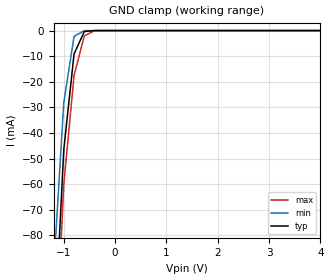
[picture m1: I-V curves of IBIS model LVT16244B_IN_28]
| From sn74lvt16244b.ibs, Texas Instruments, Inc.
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|   Model LVT16244B_IN_28
[Model]   LVT16244B_IN_28
Model_type  Input
Polarity   Non-Inverting
Vinl = 0.8
Vinh = 2.0
| variable   typ   min   max
C_comp   4p   NA   NA
[Temperature Range]   25   -40   85
[Voltage range]   2.8   2.7   2.9
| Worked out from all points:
|   GND clamp passes 1 mA (typ) near -0.61 V on its own axis
[GND Clamp]
|   Voltage   I(typ)   I(min)   I(max)
-5V       -2.158A    -2.169A    -2.264A
-1.2V     -126.5mA   -94.66mA   -144mA
-1V       -46.5mA    -28.14mA   -60.08mA
-800mV    -9.133mA   -2.237mA   -17.56mA
-600mV    -367.5uA   -43.66uA   -2.053mA
-400mV    -722.6nA   -13.95nA   -26.12uA
5V        150.8pA    8.275nA    417pA
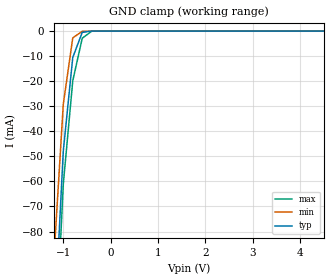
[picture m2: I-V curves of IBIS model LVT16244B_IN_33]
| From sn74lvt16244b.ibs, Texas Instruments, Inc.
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|   Model LVT16244B_IN_33
[Model]   LVT16244B_IN_33
Model_type  Input
Polarity   Non-Inverting
Vinl = 0.8
Vinh = 2.0
| variable   typ   min   max
C_comp   4p   NA   NA
[Temperature Range]   25   -40   85
[Voltage range]   3.3   3.0   3.6
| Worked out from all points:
|   GND clamp passes 1 mA (typ) near -0.61 V on its own axis
[GND Clamp]
|   Voltage   I(typ)   I(min)   I(max)
-5V       -1.808A    -1.964A    -1.81A
-1.2V     -122.6mA   -91.3mA    -140.3mA
-1V       -47.87mA   -29.15mA   -61.06mA
-800mV    -10.53mA   -2.717mA   -19.84mA
-600mV    -520.5uA   -66.75uA   -2.853mA
-400mV    -1.501uA   -57.47nA   -57.38uA
5V        654pA      352.9nA    1.202nA
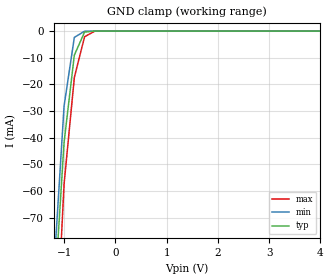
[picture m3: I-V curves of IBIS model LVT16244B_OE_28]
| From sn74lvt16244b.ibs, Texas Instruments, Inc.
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|   Model LVT16244B_OE_28
[Model]   LVT16244B_OE_28
Model_type  Input
Polarity   Non-Inverting
Vinl = 0.8
Vinh = 2.0
| variable   typ   min   max
C_comp   4p   NA   NA
[Temperature Range]   25   -40   85
[Voltage range]   2.8   2.7   2.9
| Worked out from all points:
|   GND clamp passes 1 mA (typ) near -0.61 V on its own axis
[GND Clamp]
|   Voltage   I(typ)   I(min)   I(max)
-5V       -1.782A    -1.964A    -1.89A
-1.2V     -103.1mA   -90.05mA   -134.8mA
-1V       -41.72mA   -28.1mA    -57.38mA
-800mV    -9.034mA   -2.362mA   -17.43mA
-600mV    -369.8uA   -43.6uA    -2.097mA
-400mV    -683.7nA   -55.79nA   -24.44uA
5V        543pA      94.53nA    152.2pA
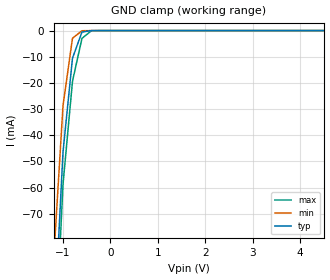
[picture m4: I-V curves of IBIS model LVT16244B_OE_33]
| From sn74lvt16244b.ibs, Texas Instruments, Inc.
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|   Model LVT16244B_OE_33
[Model]   LVT16244B_OE_33
Model_type  Input
Polarity   Non-Inverting
Vinl = 0.8
Vinh = 2.0
| variable   typ   min   max
C_comp   4p   NA   NA
[Temperature Range]   25   -40   85
[Voltage range]   3.3   3.0   3.6
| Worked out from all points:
|   GND clamp passes 1 mA (typ) near -0.61 V on its own axis
[GND Clamp]
|   Voltage   I(typ)   I(min)   I(max)
-5V       -2.067A    -2.182A    -1.86A
-1.2V     -118mA     -88.39mA   -134.3mA
-1V       -46.44mA   -28.66mA   -58.78mA
-800mV    -10.54mA   -2.926mA   -19.39mA
-600mV    -562.1uA   -66.66uA   -2.97mA
-400mV    -1.519uA   -30.87nA   -63.56uA
5V        334pA      4.395nA    173.7pA
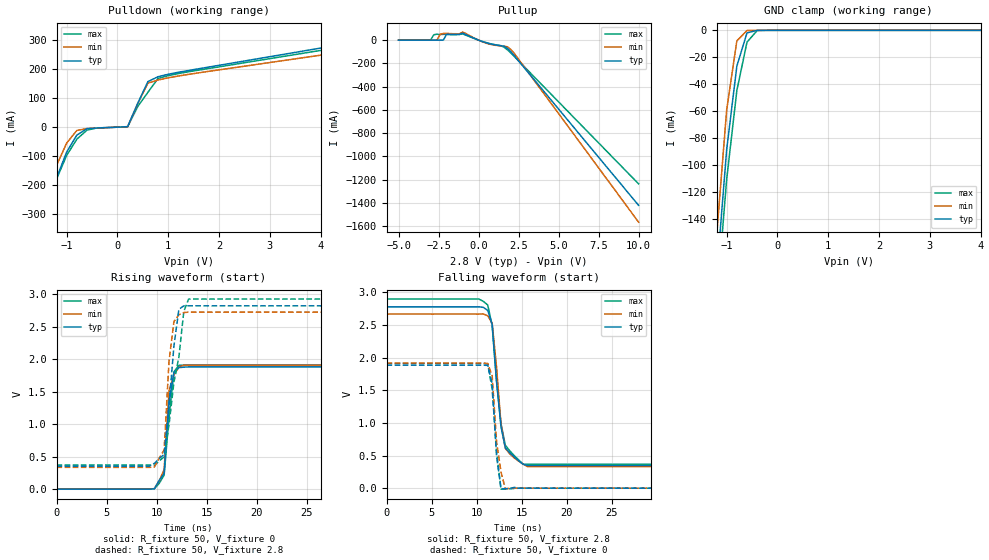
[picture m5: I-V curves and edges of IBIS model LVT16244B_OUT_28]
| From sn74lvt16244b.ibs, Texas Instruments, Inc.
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|   Model LV244A_OUT_28
[Model]   LVT16244B_OUT_28
Model_type  3-state
Polarity   Non-Inverting
Enable   Active-Low
Vmeas = 1.5
Cref = 50pf
Rref = 500
Vref = 0V
| variable   typ   min   max
C_comp   9p   NA   NA
[Temperature Range]   25   -40   85
[Voltage range]   2.8   2.7   2.9
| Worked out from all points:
|   slope of the pulldown table from 0 to 0.42 V, typ, clamps not added: 4.63 ohm
|   slope of the pullup table from 0 to 0.42 V, typ, clamps not added: 20.7 ohm
|   GND clamp passes 1 mA (typ) near -0.51 V on its own axis
|   rising waveform, R_fixture 50, V_fixture 0: 20-80 % time 606ps typ, 479ps min, 692ps max; typ from 0.004 V to 1.88 V
|   falling waveform, R_fixture 50, V_fixture 2.8: 20-80 % time 1.02ns typ, 979ps min, 1.09ns max; typ from 2.78 V to 0.35 V
|   rising waveform, R_fixture 50, V_fixture 2.8: 20-80 % time 885ps typ, 636ps min, 1.36ns max; typ from 0.357 V to 2.82 V
|   falling waveform, R_fixture 50, V_fixture 0: 20-80 % time 560ps typ, 744ps min, 646ps max; typ from 1.89 V to 0.004 V
[Pulldown]
|   Voltage   I(typ)   I(min)   I(max)
-5V       -2.032A    -1.731A    -1.883A
-1.8V     -468.9mA   -385mA     -448.5mA
-1.6V     -371.1mA   -300.8mA   -358.9mA
-1V       -86.29mA   -55.02mA   -97.82mA
-800mV    -27.55mA   -11.43mA   -41.62mA
-600mV    -5.214mA   -4.823mA   -10.29mA
200mV     1.678mA    1.694mA    1.502mA
600mV     157.7mA    152.3mA    120.7mA
800mV     174.5mA    163.2mA    168.8mA
6.4V      345.1mA    309.9mA    333.6mA
8V        392.8mA    350.6mA    379mA
10V       452.4mA    401.4mA    435.8mA
[Pullup]
|   Voltage   I(typ)   I(min)   I(max)
-5V       72.08uA    69.16uA    72.01uA
-3V       62.8uA     58.82uA    64.06uA
-2.8V     62.34uA    58.32uA    46.16mA
-2.6V     61.93uA    57.89uA    51.05mA
-2.4V     61.55uA    50.65mA    48.32mA
-2.2V     61.2uA     56.84mA    49.83mA
-2V       50.21mA    57.64mA    48.74mA
-1V       60.37mA    69.23mA    54.25mA
400mV     -19.48mA   -22.52mA   -18.42mA
1.4V      -47.56mA   -50.05mA   -48.89mA
2V        -97.67mA   -78.34mA   -108.7mA
10V       -1.422A    -1.567A    -1.237A
[GND Clamp]
|   Voltage   I(typ)   I(min)   I(max)
-5V       -2.161A    -2.101A    -1.963A
-1.2V     -183.2mA   -153.7mA   -203.3mA
-1V       -88.57mA   -59.02mA   -110.7mA
-800mV    -26.61mA   -7.837mA   -44.74mA
-600mV    -1.883mA   -140.6uA   -8.753mA
-400mV    -4.692uA   -28.08nA   -197.6uA
5V        29.91nA    20.41nA    56.24nA
[Ramp]
| variable   typ   min   max
dV/dt_r  1.134E+00/7.030E-10  1.122E+00/6.120E-10  1.182E+00/8.040E-10
dV/dt_f  1.476E+00/5.240E-10  1.413E+00/4.320E-10  1.530E+00/5.760E-10
R_load = 50
[Rising Waveform]
R_fixture = 50
V_fixture = 0
V_fixture_min = 0
V_fixture_max = 0
C_fixture = 0
L_fixture = 0
|   Time   V(typ)   V(min)   V(max)
0s        4.006mV    4.066mV    3.915mV
9.277ns   4.006mV    4.066mV    3.915mV
9.766ns   10.07mV    12.89mV    10.85mV
10.25ns   138.9mV    131.9mV    93.08mV
10.74ns   244.7mV    304.9mV    219.4mV
11.23ns   1.345V     1.518V     1.118V
11.72ns   1.798V     1.762V     1.807V
12.21ns   1.873V     1.878V     1.908V
12.7ns    1.88V      1.91V      1.91V
49.71ns   1.884V     1.91V      1.91V
[Falling Waveform]
R_fixture = 50
V_fixture = 2.8
V_fixture_min = 2.7
V_fixture_max = 2.9
C_fixture = 0pf
L_fixture = 0nH
|   Time   V(typ)   V(min)   V(max)
0s        2.777V     2.667V     2.896V
10.25ns   2.777V     2.667V     2.896V
11.23ns   2.722V     2.64V      2.805V
11.72ns   2.509V     2.527V     2.489V
12.21ns   1.638V     1.85V      1.628V
12.7ns    943mV      982.2mV    993.1mV
13.18ns   620.4mV    613.7mV    661.5mV
15.14ns   372.5mV    374.6mV    370.2mV
15.63ns   350.1mV    335.1mV    370.8mV
49.71ns   350.1mV    335.1mV    370.8mV
[Rising Waveform]
R_fixture = 50
V_fixture = 2.8
V_fixture_min = 2.7
V_fixture_max = 2.9
C_fixture = 0pf
L_fixture = 0nH
|   Time   V(typ)   V(min)   V(max)
0s        357mV      339.9mV    375.5mV
9.277ns   357mV      338.8mV    375.5mV
9.766ns   401.4mV    344.5mV    370.4mV
10.74ns   537.6mV    608.4mV    500.8mV
11.23ns   1.297V     1.977V     998.1mV
11.72ns   2.208V     2.581V     1.65V
12.21ns   2.768V     2.685V     2.03V
12.7ns    2.823V     2.719V     2.733V
13.18ns   2.823V     2.726V     2.927V
49.71ns   2.823V     2.726V     2.927V
[Falling Waveform]
R_fixture = 50
V_fixture = 0
V_fixture_min = 0
V_fixture_max = 0
C_fixture = 0pf
L_fixture = 0nH
|   Time   V(typ)   V(min)   V(max)
0s        1.885V     1.918V     1.912V
10.25ns   1.885V     1.918V     1.912V
11.23ns   1.882V     1.912V     1.901V
11.72ns   1.606V     1.724V     1.521V
12.21ns   495.5mV    707.1mV    550.5mV
12.7ns    -3.658mV   252.8mV    -10.57mV
13.18ns   -3.842mV   -4.28mV    -10.1mV
14.16ns   16.68mV    7.904mV    -557uV
14.65ns   4.073mV    4.168mV    3.957mV
49.71ns   4.073mV    4.167mV    3.957mV
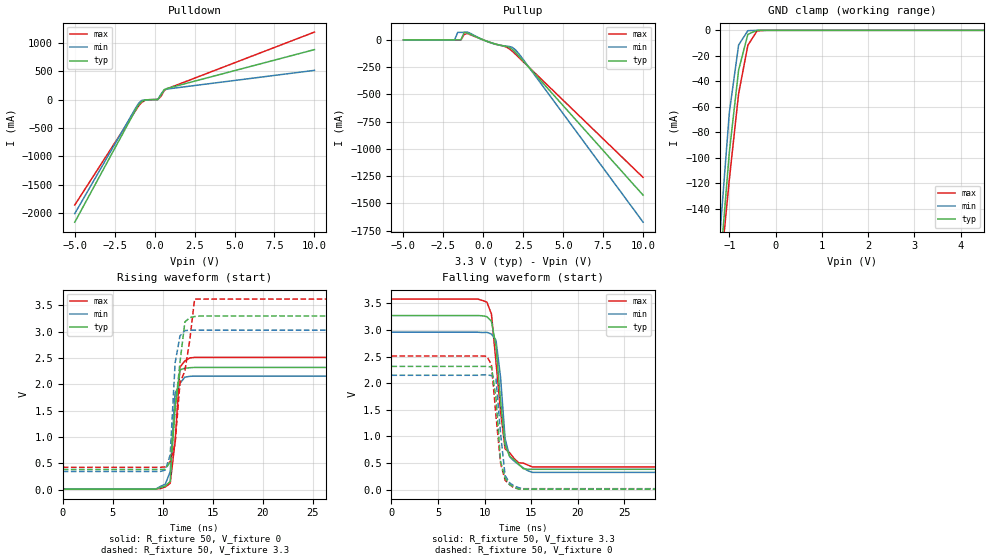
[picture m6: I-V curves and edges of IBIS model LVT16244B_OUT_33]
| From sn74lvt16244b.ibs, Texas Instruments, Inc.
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|   Model LVT16244B_OUT_33
[Model]   LVT16244B_OUT_33
Model_type  3-state
Polarity   Non-Inverting
Enable   Active-Low
Vmeas = 1.5
Cref = 50pf
Rref = 500
Vref = 0V
| variable   typ   min   max
C_comp   9p   NA   NA
[Temperature Range]   25   -40   85
[Voltage range]   3.3   3.0   3.6
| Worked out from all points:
|   slope of the pulldown table from 0 to 0.495 V, typ, clamps not added: 3.94 ohm
|   slope of the pullup table from 0 to 0.495 V, typ, clamps not added: 18.9 ohm
|   GND clamp passes 1 mA (typ) near -0.46 V on its own axis
|   rising waveform, R_fixture 50, V_fixture 0: 20-80 % time 578ps typ, 424ps min, 626ps max; typ from 0.013 V to 2.32 V
|   falling waveform, R_fixture 50, V_fixture 3.3: 20-80 % time 906ps typ, 867ps min, 1.08ns max; typ from 3.27 V to 0.384 V
|   rising waveform, R_fixture 50, V_fixture 3.3: 20-80 % time 946ps typ, 513ps min, 1.47ns max; typ from 0.386 V to 3.3 V
|   falling waveform, R_fixture 50, V_fixture 0: 20-80 % time 696ps typ, 699ps min, 798ps max; typ from 2.32 V to 0.01 V
[Pulldown]
|   Voltage   I(typ)   I(min)   I(max)
-5V       -2.155A    -2.004A    -1.853A
-1.2V     -185.4mA   -153.7mA   -196.7mA
-1V       -91.7mA    -63.67mA   -109.5mA
-800mV    -31.39mA   -13.92mA   -47.78mA
-600mV    -6.093mA   -4.894mA   -13.07mA
-400mV    -2.996mA   -3.303mA   -2.987mA
200mV     1.432mA    1.521mA    1.415mA
400mV     82.21mA    96.6mA     57.5mA
600mV     173.4mA    173.2mA    159.3mA
800mV     197.5mA    185mA      192.7mA
10V       878.3mA    513.6mA    1.186A
[Pullup]
|   Voltage   I(typ)   I(min)   I(max)
-5V       85.26uA    77.69uA    89.45uA
-1.8V     73.91uA    64.3uA     80.36uA
-1.6V     73.54uA    69.76mA    80.04uA
-1.4V     72.79uA    68.63mA    79.72uA
-1.2V     68.76mA    70.47mA    50.73mA
-1V       63.41mA    71.9mA     59.2mA
400mV     -21.6mA    -23.66mA   -21.24mA
1.4V      -58.18mA   -56.82mA   -62.44mA
1.8V      -85.21mA   -66.66mA   -102mA
2V        -112.8mA   -89.36mA   -129.2mA
2.4V      -177.2mA   -160.5mA   -186.1mA
10V       -1.425A    -1.673A    -1.262A
[GND Clamp]
|   Voltage   I(typ)   I(min)   I(max)
-5V       -1.882A    -2.095A    -1.61A
-1.2V     -184.6mA   -158.4mA   -191.3mA
-1V       -95.28mA   -64.28mA   -116.7mA
-800mV    -31.17mA   -11.52mA   -49.69mA
-600mV    -3.112mA   -274.9uA   -11.72mA
-400mV    -11.22uA   -70.83nA   -411.6uA
5V        34.75nA    19.13nA    66.41nA
[Ramp]
| variable   typ   min   max
dV/dt_r  1.488E+00/5.700E-10  1.422E+00/5.500E-10  1.662E+00/5.900E-10
dV/dt_f  1.758E+00/5.900E-10  1.624E+00/5.100E-10  1.950E+00/6.300E-10
R_load = 50
[Rising Waveform]
R_fixture = 50
V_fixture = 0
V_fixture_min = 0
V_fixture_max = 0
C_fixture = 0
L_fixture = 0
|   Time   V(typ)   V(min)   V(max)
0s        12.64mV    12.94mV    20.38mV
9.277ns   12.64mV    12.94mV    20.38mV
9.766ns   41.76mV    65.18mV    21.73mV
10.25ns   71.66mV    108mV      55.58mV
10.74ns   158.2mV    344.5mV    122.8mV
11.23ns   1.583V     1.834V     917.5mV
11.72ns   2.276V     2.021V     2.33V
12.21ns   2.309V     2.14V      2.449V
12.7ns    2.318V     2.154V     2.504V
49.71ns   2.323V     2.159V     2.514V
[Falling Waveform]
R_fixture = 50
V_fixture = 3.3
V_fixture_min = 3
V_fixture_max = 3.6
C_fixture = 0pf
L_fixture = 0nH
|   Time   V(typ)   V(min)   V(max)
0s        3.272V     2.959V     3.582V
10.25ns   3.252V     2.956V     3.525V
10.74ns   3.166V     2.925V     3.303V
11.23ns   2.696V     2.808V     2.403V
11.72ns   1.674V     2.115V     1.478V
12.21ns   837.1mV    957.4mV    766.5mV
12.7ns    627.9mV    620.3mV    696.3mV
13.67ns   480.2mV    470.7mV    504.9mV
15.14ns   383.6mV    325.6mV    428.1mV
49.71ns   383.6mV    325.6mV    428.1mV
[Rising Waveform]
R_fixture = 50
V_fixture = 3.3
V_fixture_min = 3
V_fixture_max = 3.6
C_fixture = 0pf
L_fixture = 0nH
|   Time   V(typ)   V(min)   V(max)
0s        386.3mV    349.2mV    427.7mV
9.766ns   386.3mV    349.2mV    427.7mV
10.25ns   391.8mV    375.5mV    434.8mV
10.74ns   529.8mV    662.7mV    539.9mV
11.23ns   1.498V     2.403V     877.9mV
11.72ns   2.425V     2.924V     2.027V
12.21ns   3.186V     3.022V     2.259V
12.7ns    3.27V      3.03V      2.845V
13.18ns   3.289V     3.03V      3.621V
49.71ns   3.3V       3.03V      3.621V
[Falling Waveform]
R_fixture = 50
V_fixture = 0
V_fixture_min = 0
V_fixture_max = 0
C_fixture = 0pf
L_fixture = 0nH
|   Time   V(typ)   V(min)   V(max)
0s        2.317V     2.15V      2.512V
10.25ns   2.318V     2.156V     2.507V
10.74ns   2.306V     2.145V     2.351V
11.23ns   1.726V     2.086V     1.389V
11.72ns   534.5mV    1.062V     500mV
12.21ns   214.7mV    265.5mV    178.6mV
12.7ns    93.09mV    128.8mV    95.22mV
13.18ns   45.46mV    69.1mV     31.28mV
14.16ns   10.14mV    12.09mV    18.79mV
49.71ns   10.14mV    12.09mV    18.79mV
